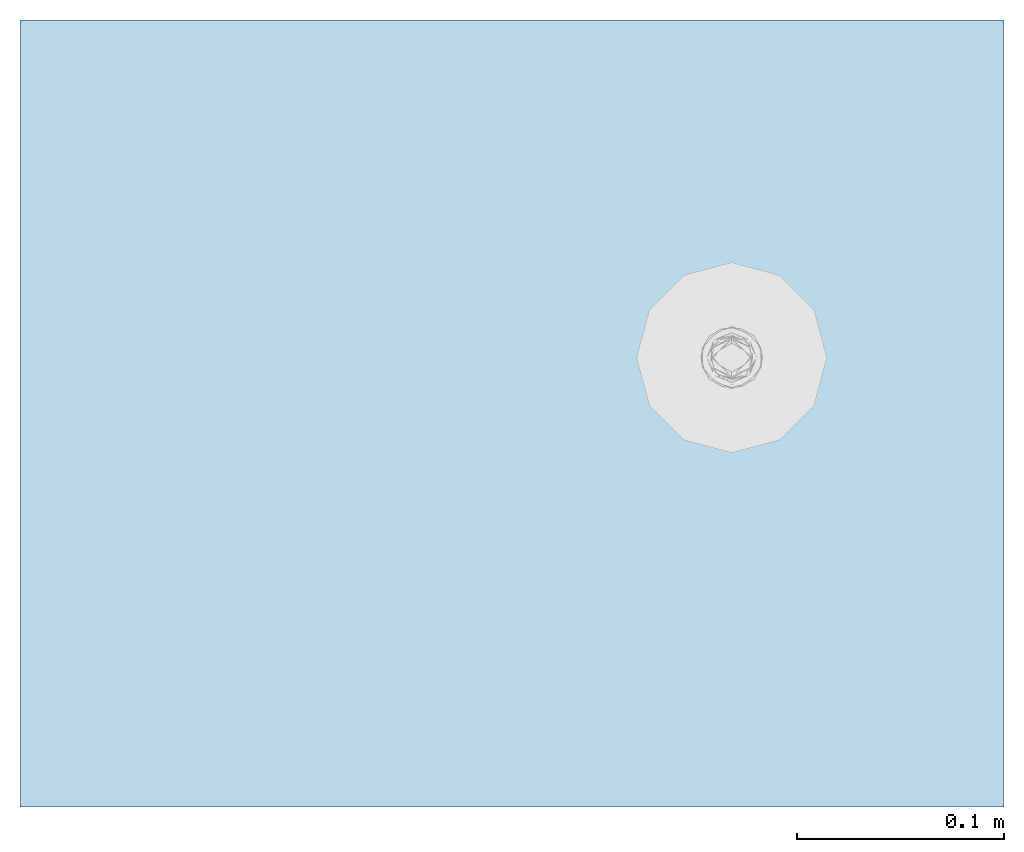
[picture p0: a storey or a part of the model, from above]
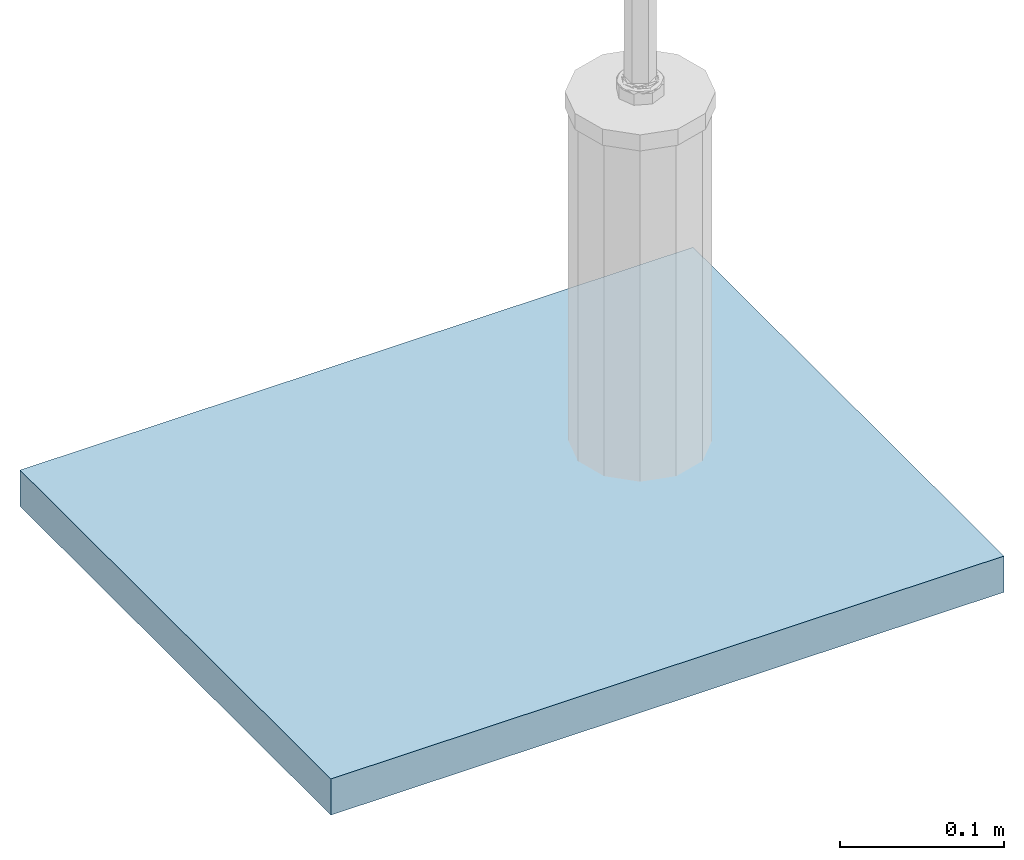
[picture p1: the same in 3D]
Properties of the parts of a building model (IFC2X3)

# File
Description: ViewDefinition [CoordinationView]
Time: 2017-05-16T15:04:20
Written by: The EXPRESS Data Manager Version 5.01.0100.02.64mod : 6 Jun 2012
Made in: 20140709_2115(x64) - Exporter 2014.0.2014.0709 - Default UI
Comment: STEP Physical File produced by: The EXPRESS Data Manager Version 5.01.0100.02.64mod : 6 Jun 2012 * Module: EDMstepFileFactory/EDMstandAlone * Creation date: Tue May 16 15:04:20 2017 * Host: BIM-HP * Database: C:\Users\dcole\AppData\Local\Temp\{F426136A-FD19-4B54-B72F-8C22015C433A}\ifc * Database version: 5507 * Database creation date: Tue May 16 15:04:18 2017 * Schema: IFC2X3 * Model: DataRepository.ifc * Model creation date: Tue May 16 15:04:19 2017 * Header model: DataRepository.ifc_HeaderModel * Header model creation date: Tue May 16 15:04:19 2017 * EDMuser: sdai-user * EDMgroup: sdai-group * License ID and type: 5605 : Permanent license. Expiry date: * EDMstepFileFactory options: 020000

# IfcProject
LongName: P:\Fastrack\53721_BELL-CHEM\ADDITIONAL DRAWINGS 2017 BIM\IFC\BC723.ifc

# IfcSite, Default
RefLatitude: 42, 24, 53, 508911; RefLongitude: -71, -15, -29, -58837; RefElevation: 0 mm

# IfcBuilding
Pset_BuildingCommon - NumberOfStoreys: 1

# IfcBuildingStorey, Level 1
LongName: Level 1; Elevation: 0 mm
Constraints - Elevation Base: Project Base Point; Elevation: 0 mm
Identity Data - Building Story: yes; Name: Level 1; Structural: no
Dimensions - Computation Height: 0 mm
Graphics - Line Weight: 1; Symbol at End 2 Default: yes; Symbol at End 1 Default: no; Color: 0; Line Pattern: -3000010

# IfcBuildingElementProxy: BC723 Dolphin Freestanding Toilet Brush Set, BC723:BC723 Dolphin Freestanding Toilet Brush Set:8305
In: Level 1
Material: Stainless Steel
Phasing - Phase Created: New Construction
Constraints - Moves With Nearby Elements: no; Host: Level : Level 1; Level: Level: Level 1; Offset: 255.101 mm
Dimensions - Volume: 0.00163755 m3; Projection: ø88mm; Height: 391mm
Pset_ManufacturerTypeInformation - Manufacturer: Dolphin Solutions Ltd.
Pset_BuildingElementProxyCommon - Reference: BC723 Dolphin Freestanding Toilet Brush Set
Identity Data - Manufacturer: Dolphin Solutions Ltd.; Type Comments: For wall mounted version see BC727; URL: www.dolphinsolutions.co.uk; Tel No.: +44 (0) 1424 202 224; Address: Southpoint, Compass Park, Junction Road, Bodiam, TN32 5BS; Model: BC723; Assembly Code: D2010900; Assembly Description: Other Plumbing Fixtures; Description: Freestanding toilet brush set; Fax No.: +44 (0) 1424 205 200; Email: info@dolphinsolutions.co.uk
General - Product Data: Timeless design for prestigious appearance in high class enviroments. 304 stainless steel for easy care and durability. Available in satin (brushed) stainless steel to compliment other Dolphin products. Replaceable nylon brush head. Plastic inner container, removable for emptying/cleaning.; Product Page Link: https://www.dolphinsolutions.co.uk/product/freestanding-toilet-brush-set/

# IfcSlab: Floor:Counter, Floor:Counter:2279
In: Level 1
PredefinedType: FLOOR; Material: Analytical Floor Surface 27 mm
Dimensions - Area: 0.1805 m2; Volume: 0.0048735 m3; Perimeter: 1710 mm; Thickness: 27 mm
Structural - Enable Analytical Model: no; Structural: no
Phasing - Phase Created: New Construction
Constraints - Height Offset From Level: 0 mm; Room Bounding: yes; Level: Level: Level 1; Related to Mass: no
Pset_SlabCommon - Reference: Counter; IsExternal: no; LoadBearing: yes; PitchAngle: 0 deg
Analytical Properties - Roughness: 1; Absorptance: 0.1
Graphics - Coarse Scale Fill Pattern: Solid fill; Coarse Scale Fill Color: 8454143
Construction - Default Thickness: 27 mm
